One B-rep face of a CAD part: STEP entity #46566.
In plain terms, the planar face has unit normal (0, 0, 1).
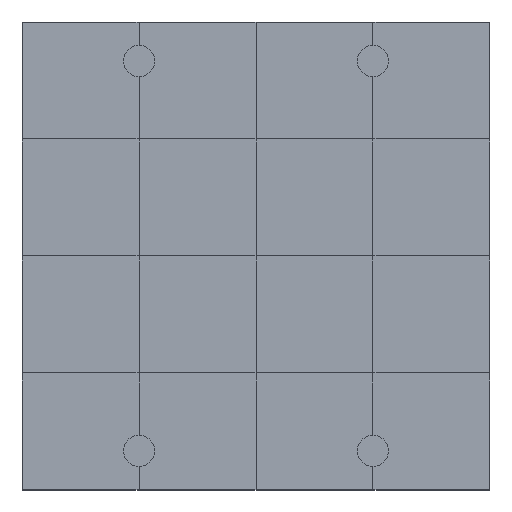
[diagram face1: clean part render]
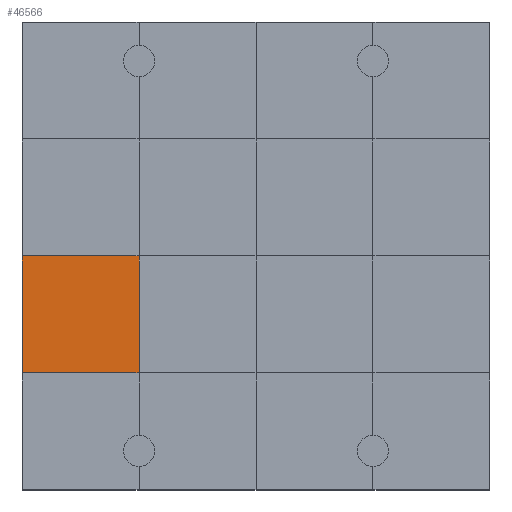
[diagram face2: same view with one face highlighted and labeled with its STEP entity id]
Its self-contained STEP definition (entity closure, numbers rounded to 3 decimals):
#46116 = VERTEX_POINT('',#46117);
#46117 = CARTESIAN_POINT('',(0.,3.,1.2));
#46131 = PLANE('',#46132);
#46132 = AXIS2_PLACEMENT_3D('',#46133,#46134,#46135);
#46133 = CARTESIAN_POINT('',(0.,3.,0.));
#46134 = DIRECTION('',(1.,0.,-0.));
#46135 = DIRECTION('',(0.,0.,1.));
#46157 = PLANE('',#46158);
#46158 = AXIS2_PLACEMENT_3D('',#46159,#46160,#46161);
#46159 = CARTESIAN_POINT('',(0.,0.,1.2));
#46160 = DIRECTION('',(0.,0.,1.));
#46161 = DIRECTION('',(1.,0.,-0.));
#46308 = VERTEX_POINT('',#46309);
#46309 = CARTESIAN_POINT('',(3.,3.,1.2));
#46330 = EDGE_CURVE('',#46116,#46308,#46331,.T.);
#46331 = SURFACE_CURVE('',#46332,(#46336,#46343),.PCURVE_S1.);
#46332 = LINE('',#46333,#46334);
#46333 = CARTESIAN_POINT('',(0.,3.,1.2));
#46334 = VECTOR('',#46335,1.);
#46335 = DIRECTION('',(1.,0.,-0.));
#46336 = PCURVE('',#46157,#46337);
#46337 = DEFINITIONAL_REPRESENTATION('',(#46338),#46342);
#46338 = LINE('',#46339,#46340);
#46339 = CARTESIAN_POINT('',(0.,3.));
#46340 = VECTOR('',#46341,1.);
#46341 = DIRECTION('',(1.,0.));
#46342 = ( GEOMETRIC_REPRESENTATION_CONTEXT(2) 
PARAMETRIC_REPRESENTATION_CONTEXT() REPRESENTATION_CONTEXT('2D SPACE',''
  ) );
#46343 = PCURVE('',#46344,#46349);
#46344 = PLANE('',#46345);
#46345 = AXIS2_PLACEMENT_3D('',#46346,#46347,#46348);
#46346 = CARTESIAN_POINT('',(0.,3.,1.2));
#46347 = DIRECTION('',(0.,0.,1.));
#46348 = DIRECTION('',(1.,0.,-0.));
#46349 = DEFINITIONAL_REPRESENTATION('',(#46350),#46354);
#46350 = LINE('',#46351,#46352);
#46351 = CARTESIAN_POINT('',(0.,0.));
#46352 = VECTOR('',#46353,1.);
#46353 = DIRECTION('',(1.,0.));
#46354 = ( GEOMETRIC_REPRESENTATION_CONTEXT(2) 
PARAMETRIC_REPRESENTATION_CONTEXT() REPRESENTATION_CONTEXT('2D SPACE',''
  ) );
#46389 = VERTEX_POINT('',#46390);
#46390 = CARTESIAN_POINT('',(0.,6.,1.2));
#46416 = EDGE_CURVE('',#46116,#46389,#46417,.T.);
#46417 = SURFACE_CURVE('',#46418,(#46422,#46429),.PCURVE_S1.);
#46418 = LINE('',#46419,#46420);
#46419 = CARTESIAN_POINT('',(0.,3.,1.2));
#46420 = VECTOR('',#46421,1.);
#46421 = DIRECTION('',(-0.,1.,0.));
#46422 = PCURVE('',#46131,#46423);
#46423 = DEFINITIONAL_REPRESENTATION('',(#46424),#46428);
#46424 = LINE('',#46425,#46426);
#46425 = CARTESIAN_POINT('',(1.2,0.));
#46426 = VECTOR('',#46427,1.);
#46427 = DIRECTION('',(0.,-1.));
#46428 = ( GEOMETRIC_REPRESENTATION_CONTEXT(2) 
PARAMETRIC_REPRESENTATION_CONTEXT() REPRESENTATION_CONTEXT('2D SPACE',''
  ) );
#46429 = PCURVE('',#46344,#46430);
#46430 = DEFINITIONAL_REPRESENTATION('',(#46431),#46435);
#46431 = LINE('',#46432,#46433);
#46432 = CARTESIAN_POINT('',(0.,0.));
#46433 = VECTOR('',#46434,1.);
#46434 = DIRECTION('',(0.,1.));
#46435 = ( GEOMETRIC_REPRESENTATION_CONTEXT(2) 
PARAMETRIC_REPRESENTATION_CONTEXT() REPRESENTATION_CONTEXT('2D SPACE',''
  ) );
#46566 = ADVANCED_FACE('',(#46567),#46344,.T.);
#46567 = FACE_BOUND('',#46568,.T.);
#46568 = EDGE_LOOP('',(#46569,#46570,#46571,#46599));
#46569 = ORIENTED_EDGE('',*,*,#46416,.F.);
#46570 = ORIENTED_EDGE('',*,*,#46330,.T.);
#46571 = ORIENTED_EDGE('',*,*,#46572,.T.);
#46572 = EDGE_CURVE('',#46308,#46573,#46575,.T.);
#46573 = VERTEX_POINT('',#46574);
#46574 = CARTESIAN_POINT('',(3.,6.,1.2));
#46575 = SURFACE_CURVE('',#46576,(#46580,#46587),.PCURVE_S1.);
#46576 = LINE('',#46577,#46578);
#46577 = CARTESIAN_POINT('',(3.,3.,1.2));
#46578 = VECTOR('',#46579,1.);
#46579 = DIRECTION('',(-0.,1.,0.));
#46580 = PCURVE('',#46344,#46581);
#46581 = DEFINITIONAL_REPRESENTATION('',(#46582),#46586);
#46582 = LINE('',#46583,#46584);
#46583 = CARTESIAN_POINT('',(3.,0.));
#46584 = VECTOR('',#46585,1.);
#46585 = DIRECTION('',(0.,1.));
#46586 = ( GEOMETRIC_REPRESENTATION_CONTEXT(2) 
PARAMETRIC_REPRESENTATION_CONTEXT() REPRESENTATION_CONTEXT('2D SPACE',''
  ) );
#46587 = PCURVE('',#46588,#46593);
#46588 = PLANE('',#46589);
#46589 = AXIS2_PLACEMENT_3D('',#46590,#46591,#46592);
#46590 = CARTESIAN_POINT('',(3.,3.,1.2));
#46591 = DIRECTION('',(0.,0.,1.));
#46592 = DIRECTION('',(1.,0.,-0.));
#46593 = DEFINITIONAL_REPRESENTATION('',(#46594),#46598);
#46594 = LINE('',#46595,#46596);
#46595 = CARTESIAN_POINT('',(0.,0.));
#46596 = VECTOR('',#46597,1.);
#46597 = DIRECTION('',(0.,1.));
#46598 = ( GEOMETRIC_REPRESENTATION_CONTEXT(2) 
PARAMETRIC_REPRESENTATION_CONTEXT() REPRESENTATION_CONTEXT('2D SPACE',''
  ) );
#46599 = ORIENTED_EDGE('',*,*,#46600,.F.);
#46600 = EDGE_CURVE('',#46389,#46573,#46601,.T.);
#46601 = SURFACE_CURVE('',#46602,(#46606,#46613),.PCURVE_S1.);
#46602 = LINE('',#46603,#46604);
#46603 = CARTESIAN_POINT('',(0.,6.,1.2));
#46604 = VECTOR('',#46605,1.);
#46605 = DIRECTION('',(1.,0.,-0.));
#46606 = PCURVE('',#46344,#46607);
#46607 = DEFINITIONAL_REPRESENTATION('',(#46608),#46612);
#46608 = LINE('',#46609,#46610);
#46609 = CARTESIAN_POINT('',(0.,3.));
#46610 = VECTOR('',#46611,1.);
#46611 = DIRECTION('',(1.,0.));
#46612 = ( GEOMETRIC_REPRESENTATION_CONTEXT(2) 
PARAMETRIC_REPRESENTATION_CONTEXT() REPRESENTATION_CONTEXT('2D SPACE',''
  ) );
#46613 = PCURVE('',#46614,#46619);
#46614 = PLANE('',#46615);
#46615 = AXIS2_PLACEMENT_3D('',#46616,#46617,#46618);
#46616 = CARTESIAN_POINT('',(0.,6.,1.2));
#46617 = DIRECTION('',(0.,0.,1.));
#46618 = DIRECTION('',(1.,0.,-0.));
#46619 = DEFINITIONAL_REPRESENTATION('',(#46620),#46624);
#46620 = LINE('',#46621,#46622);
#46621 = CARTESIAN_POINT('',(0.,0.));
#46622 = VECTOR('',#46623,1.);
#46623 = DIRECTION('',(1.,0.));
#46624 = ( GEOMETRIC_REPRESENTATION_CONTEXT(2) 
PARAMETRIC_REPRESENTATION_CONTEXT() REPRESENTATION_CONTEXT('2D SPACE',''
  ) );
